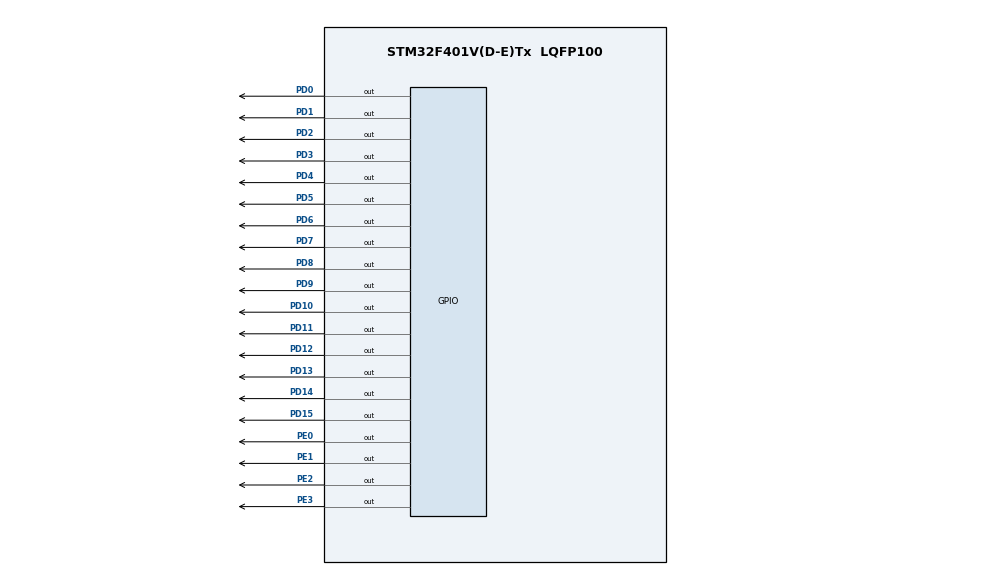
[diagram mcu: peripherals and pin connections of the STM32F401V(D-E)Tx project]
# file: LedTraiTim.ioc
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Mcu.Family=STM32F4
Mcu.Name=STM32F401V(D-E)Tx
Mcu.Package=LQFP100
NVIC.PriorityGroup=NVIC_PRIORITYGROUP_4
PD0.GPIO_Speed=GPIO_SPEED_FREQ_HIGH
PD0.PinState=GPIO_PIN_RESET
PD0.Signal=GPIO_Output
PD1.GPIO_Speed=GPIO_SPEED_FREQ_HIGH
PD1.Signal=GPIO_Output
PD10.GPIO_Speed=GPIO_SPEED_FREQ_HIGH
PD10.Signal=GPIO_Output
PD11.GPIO_Speed=GPIO_SPEED_FREQ_HIGH
PD11.Signal=GPIO_Output
PD12.GPIO_Speed=GPIO_SPEED_FREQ_HIGH
PD12.Signal=GPIO_Output
PD13.GPIO_Speed=GPIO_SPEED_FREQ_HIGH
PD13.Signal=GPIO_Output
PD14.GPIO_Speed=GPIO_SPEED_FREQ_HIGH
PD14.Signal=GPIO_Output
PD15.GPIO_Speed=GPIO_SPEED_FREQ_HIGH
PD15.Signal=GPIO_Output
PD2.GPIO_Speed=GPIO_SPEED_FREQ_HIGH
PD2.Signal=GPIO_Output
PD3.GPIO_Speed=GPIO_SPEED_FREQ_MEDIUM
PD3.Signal=GPIO_Output
PD4.GPIO_Speed=GPIO_SPEED_FREQ_HIGH
PD4.Signal=GPIO_Output
PD5.GPIO_Speed=GPIO_SPEED_FREQ_HIGH
PD5.Signal=GPIO_Output
PD6.GPIO_Speed=GPIO_SPEED_FREQ_HIGH
PD6.Signal=GPIO_Output
PD7.GPIO_Speed=GPIO_SPEED_FREQ_HIGH
PD7.Signal=GPIO_Output
PD8.GPIO_Speed=GPIO_SPEED_FREQ_HIGH
PD8.Signal=GPIO_Output
PD9.GPIO_Speed=GPIO_SPEED_FREQ_HIGH
PD9.Signal=GPIO_Output
PE0.GPIO_Speed=GPIO_SPEED_FREQ_HIGH
PE0.Signal=GPIO_Output
PE1.GPIO_Speed=GPIO_SPEED_FREQ_HIGH
PE1.Signal=GPIO_Output
PE2.GPIO_Speed=GPIO_SPEED_FREQ_HIGH
PE2.Signal=GPIO_Output
PE3.GPIO_Speed=GPIO_SPEED_FREQ_HIGH
PE3.Signal=GPIO_Output
PH0\ -\ OSC_IN.Mode=HSE-External-Oscillator
PH0\ -\ OSC_IN.Signal=RCC_OSC_IN
PH1\ -\ OSC_OUT.Mode=HSE-External-Oscillator
PH1\ -\ OSC_OUT.Signal=RCC_OSC_OUT
ProjectManager.HeapSize=0x200
ProjectManager.StackSize=0x400
ProjectManager.TargetToolchain=MDK-ARM V5.32
RCC.AHBFreq_Value=25000000
RCC.APB1Freq_Value=25000000
RCC.APB1TimFreq_Value=25000000
RCC.APB2Freq_Value=25000000
RCC.APB2TimFreq_Value=25000000
RCC.CortexFreq_Value=25000000
RCC.HCLKFreq_Value=25000000
RCC.HSE_VALUE=25000000
RCC.HSI_VALUE=16000000
RCC.LSE_VALUE=32768
RCC.SYSCLKFreq_VALUE=25000000
RCC.SYSCLKSource=RCC_SYSCLKSOURCE_HSE
RCC.VCOOutputFreq_Value=192000000
board=custom

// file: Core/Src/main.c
/* USER CODE BEGIN Header */
/**
  ******************************************************************************
  * @file           : main.c
  * @brief          : Main program body
  ******************************************************************************
  * @attention
  *
  * <h2><center>&copy; Copyright (c) 2021 STMicroelectronics.
  * All rights reserved.</center></h2>
  *
  * This software component is licensed by ST under BSD 3-Clause license,
  * the "License"; You may not use this file except in compliance with the
  * License. You may obtain a copy of the License at:
  *                        opensource.org/licenses/BSD-3-Clause
  *
  ******************************************************************************
  */
/* USER CODE END Header */
#include "main.h"

void SystemClock_Config(void);
static void MX_GPIO_Init(void);

void Sangden();
void Tatden();
void Sanglanluot1();
void Sanglanluot2();
int main(void)
{
  HAL_Init();
  SystemClock_Config();
  MX_GPIO_Init();
  while (1)
  {
		Sangden();
		HAL_Delay(100);
		Tatden();
		HAL_Delay(100);
		Sanglanluot1();
		HAL_Delay(100);
		Sanglanluot2();

  }
}

void Sangden(){
	HAL_GPIO_WritePin (GPIOD, GPIO_PIN_0, GPIO_PIN_SET);
	HAL_GPIO_WritePin (GPIOD, GPIO_PIN_1, GPIO_PIN_SET);
	HAL_GPIO_WritePin (GPIOD, GPIO_PIN_2, GPIO_PIN_SET);
	HAL_GPIO_WritePin (GPIOD, GPIO_PIN_3, GPIO_PIN_SET);
	HAL_GPIO_WritePin (GPIOD, GPIO_PIN_4, GPIO_PIN_SET);
	HAL_GPIO_WritePin (GPIOD, GPIO_PIN_5, GPIO_PIN_SET);
	HAL_GPIO_WritePin (GPIOD, GPIO_PIN_6, GPIO_PIN_SET);
	HAL_GPIO_WritePin (GPIOD, GPIO_PIN_7, GPIO_PIN_SET);
	HAL_GPIO_WritePin (GPIOD, GPIO_PIN_8, GPIO_PIN_SET);
	HAL_GPIO_WritePin (GPIOD, GPIO_PIN_9, GPIO_PIN_SET);
	HAL_GPIO_WritePin (GPIOD, GPIO_PIN_10, GPIO_PIN_SET);
	HAL_GPIO_WritePin (GPIOD, GPIO_PIN_11, GPIO_PIN_SET);
	HAL_GPIO_WritePin (GPIOD, GPIO_PIN_12, GPIO_PIN_SET);
	HAL_GPIO_WritePin (GPIOD, GPIO_PIN_13, GPIO_PIN_SET);
	HAL_GPIO_WritePin (GPIOD, GPIO_PIN_14, GPIO_PIN_SET);
	HAL_GPIO_WritePin (GPIOD, GPIO_PIN_15, GPIO_PIN_SET);

	HAL_GPIO_WritePin (GPIOE, GPIO_PIN_0, GPIO_PIN_SET);
	HAL_GPIO_WritePin (GPIOE, GPIO_PIN_1, GPIO_PIN_SET);
	HAL_GPIO_WritePin (GPIOE, GPIO_PIN_2, GPIO_PIN_SET);
	HAL_GPIO_WritePin (GPIOE, GPIO_PIN_3, GPIO_PIN_SET);
}

void Tatden(){
	HAL_GPIO_WritePin (GPIOD, GPIO_PIN_0, GPIO_PIN_RESET);
	HAL_GPIO_WritePin (GPIOD, GPIO_PIN_1, GPIO_PIN_RESET);
	HAL_GPIO_WritePin (GPIOD, GPIO_PIN_2, GPIO_PIN_RESET);
	HAL_GPIO_WritePin (GPIOD, GPIO_PIN_3, GPIO_PIN_RESET);
	HAL_GPIO_WritePin (GPIOD, GPIO_PIN_4, GPIO_PIN_RESET);
	HAL_GPIO_WritePin (GPIOD, GPIO_PIN_5, GPIO_PIN_RESET);
	HAL_GPIO_WritePin (GPIOD, GPIO_PIN_6, GPIO_PIN_RESET);
	HAL_GPIO_WritePin (GPIOD, GPIO_PIN_7, GPIO_PIN_RESET);
	HAL_GPIO_WritePin (GPIOD, GPIO_PIN_8, GPIO_PIN_RESET);
	HAL_GPIO_WritePin (GPIOD, GPIO_PIN_9, GPIO_PIN_RESET);
	HAL_GPIO_WritePin (GPIOD, GPIO_PIN_10, GPIO_PIN_RESET);
	HAL_GPIO_WritePin (GPIOD, GPIO_PIN_11, GPIO_PIN_RESET);
	HAL_GPIO_WritePin (GPIOD, GPIO_PIN_12, GPIO_PIN_RESET);
	HAL_GPIO_WritePin (GPIOD, GPIO_PIN_13, GPIO_PIN_RESET);
	HAL_GPIO_WritePin (GPIOD, GPIO_PIN_14, GPIO_PIN_RESET);
	HAL_GPIO_WritePin (GPIOD, GPIO_PIN_15, GPIO_PIN_RESET);

	HAL_GPIO_WritePin (GPIOE, GPIO_PIN_0, GPIO_PIN_RESET);
	HAL_GPIO_WritePin (GPIOE, GPIO_PIN_1, GPIO_PIN_RESET);
	HAL_GPIO_WritePin (GPIOE, GPIO_PIN_2, GPIO_PIN_RESET);
	HAL_GPIO_WritePin (GPIOE, GPIO_PIN_3, GPIO_PIN_RESET);
}

void Sanglanluot1(){
	Tatden();
	HAL_Delay(100);
	HAL_GPIO_WritePin (GPIOD, GPIO_PIN_0, GPIO_PIN_SET);
	HAL_Delay(100);
	HAL_GPIO_WritePin (GPIOD, GPIO_PIN_1, GPIO_PIN_SET);
	HAL_Delay(100);
	HAL_GPIO_WritePin (GPIOD, GPIO_PIN_2, GPIO_PIN_SET);
	HAL_Delay(100);
	HAL_GPIO_WritePin (GPIOD, GPIO_PIN_3, GPIO_PIN_SET);
	HAL_Delay(100);
	HAL_GPIO_WritePin (GPIOD, GPIO_PIN_4, GPIO_PIN_SET);
	HAL_Delay(100);
	HAL_GPIO_WritePin (GPIOD, GPIO_PIN_5, GPIO_PIN_SET);
	HAL_Delay(100);
	HAL_GPIO_WritePin (GPIOD, GPIO_PIN_6, GPIO_PIN_SET);
	HAL_Delay(100);
	HAL_GPIO_WritePin (GPIOD, GPIO_PIN_7, GPIO_PIN_SET);
	HAL_Delay(100);
	HAL_GPIO_WritePin (GPIOD, GPIO_PIN_8, GPIO_PIN_SET);
	HAL_Delay(100);
	HAL_GPIO_WritePin (GPIOD, GPIO_PIN_9, GPIO_PIN_SET);
	HAL_Delay(100);
	HAL_GPIO_WritePin (GPIOD, GPIO_PIN_10, GPIO_PIN_SET);
	HAL_Delay(100);
	HAL_GPIO_WritePin (GPIOD, GPIO_PIN_11, GPIO_PIN_SET);
	HAL_Delay(100);
	HAL_GPIO_WritePin (GPIOD, GPIO_PIN_12, GPIO_PIN_SET);
	HAL_Delay(100);
	HAL_GPIO_WritePin (GPIOD, GPIO_PIN_13, GPIO_PIN_SET);
	HAL_Delay(100);
	HAL_GPIO_WritePin (GPIOD, GPIO_PIN_14, GPIO_PIN_SET);
	HAL_Delay(100);
	HAL_GPIO_WritePin (GPIOD, GPIO_PIN_15, GPIO_PIN_SET);
	HAL_Delay(100);
	HAL_GPIO_WritePin (GPIOE, GPIO_PIN_0, GPIO_PIN_SET);
	HAL_Delay(100);
	HAL_GPIO_WritePin (GPIOE, GPIO_PIN_1, GPIO_PIN_SET);
	HAL_Delay(100);
	HAL_GPIO_WritePin (GPIOE, GPIO_PIN_2, GPIO_PIN_SET);
	HAL_Delay(100);
	HAL_GPIO_WritePin (GPIOE, GPIO_PIN_3, GPIO_PIN_SET);
	HAL_Delay(100);
}
void Sanglanluot2(){
		Tatden();
	HAL_Delay(100);

	HAL_GPIO_WritePin (GPIOD, GPIO_PIN_0, GPIO_PIN_SET);
	HAL_Delay(100);
	HAL_GPIO_WritePin (GPIOD, GPIO_PIN_0, GPIO_PIN_RESET);

	HAL_GPIO_WritePin (GPIOD, GPIO_PIN_1, GPIO_PIN_SET);
	HAL_Delay(100);
	HAL_GPIO_WritePin (GPIOD, GPIO_PIN_1, GPIO_PIN_RESET);

	HAL_GPIO_WritePin (GPIOD, GPIO_PIN_2, GPIO_PIN_SET);
	HAL_Delay(100);
	HAL_GPIO_WritePin (GPIOD, GPIO_PIN_2, GPIO_PIN_RESET);

	HAL_GPIO_WritePin (GPIOD, GPIO_PIN_3, GPIO_PIN_SET);
	HAL_Delay(100);
	HAL_GPIO_WritePin (GPIOD, GPIO_PIN_3, GPIO_PIN_RESET);

	HAL_GPIO_WritePin (GPIOD, GPIO_PIN_4, GPIO_PIN_SET);
	HAL_Delay(100);
	HAL_GPIO_WritePin (GPIOD, GPIO_PIN_4, GPIO_PIN_RESET);

	HAL_GPIO_WritePin (GPIOD, GPIO_PIN_5, GPIO_PIN_SET);
	HAL_Delay(100);
	HAL_GPIO_WritePin (GPIOD, GPIO_PIN_5, GPIO_PIN_RESET);

	HAL_GPIO_WritePin (GPIOD, GPIO_PIN_6, GPIO_PIN_SET);
	HAL_Delay(100);
	HAL_GPIO_WritePin (GPIOD, GPIO_PIN_6, GPIO_PIN_RESET);

	HAL_GPIO_WritePin (GPIOD, GPIO_PIN_7, GPIO_PIN_SET);
	HAL_Delay(100);
	HAL_GPIO_WritePin (GPIOD, GPIO_PIN_7, GPIO_PIN_RESET);

	HAL_GPIO_WritePin (GPIOD, GPIO_PIN_8, GPIO_PIN_SET);
	HAL_Delay(100);
	HAL_GPIO_WritePin (GPIOD, GPIO_PIN_8, GPIO_PIN_RESET);

	HAL_GPIO_WritePin (GPIOD, GPIO_PIN_9, GPIO_PIN_SET);
	HAL_Delay(100);
	HAL_GPIO_WritePin (GPIOD, GPIO_PIN_9, GPIO_PIN_RESET);

	HAL_GPIO_WritePin (GPIOD, GPIO_PIN_10, GPIO_PIN_SET);
	HAL_Delay(100);
	HAL_GPIO_WritePin (GPIOD, GPIO_PIN_10, GPIO_PIN_RESET);

	HAL_GPIO_WritePin (GPIOD, GPIO_PIN_11, GPIO_PIN_SET);
	HAL_Delay(100);
	HAL_GPIO_WritePin (GPIOD, GPIO_PIN_11, GPIO_PIN_RESET);

	HAL_GPIO_WritePin (GPIOD, GPIO_PIN_12, GPIO_PIN_SET);
	HAL_Delay(100);
	HAL_GPIO_WritePin (GPIOD, GPIO_PIN_12, GPIO_PIN_RESET);

	HAL_GPIO_WritePin (GPIOD, GPIO_PIN_13, GPIO_PIN_SET);
	HAL_Delay(100);
	HAL_GPIO_WritePin (GPIOD, GPIO_PIN_13, GPIO_PIN_RESET);

	HAL_GPIO_WritePin (GPIOD, GPIO_PIN_14, GPIO_PIN_SET);
	HAL_Delay(100);
	HAL_GPIO_WritePin (GPIOD, GPIO_PIN_14, GPIO_PIN_RESET);

	HAL_GPIO_WritePin (GPIOD, GPIO_PIN_15, GPIO_PIN_SET);
	HAL_Delay(100);
	HAL_GPIO_WritePin (GPIOD, GPIO_PIN_15, GPIO_PIN_RESET);

	HAL_GPIO_WritePin (GPIOE, GPIO_PIN_0, GPIO_PIN_SET);
	HAL_Delay(100);
	HAL_GPIO_WritePin (GPIOE, GPIO_PIN_0, GPIO_PIN_RESET);

	HAL_GPIO_WritePin (GPIOE, GPIO_PIN_1, GPIO_PIN_SET);
	HAL_Delay(100);
	HAL_GPIO_WritePin (GPIOE, GPIO_PIN_1, GPIO_PIN_RESET);

	HAL_GPIO_WritePin (GPIOE, GPIO_PIN_2, GPIO_PIN_SET);
	HAL_Delay(100);
	HAL_GPIO_WritePin (GPIOE, GPIO_PIN_2, GPIO_PIN_RESET);

	HAL_GPIO_WritePin (GPIOE, GPIO_PIN_3, GPIO_PIN_SET);
	HAL_Delay(100);
	HAL_GPIO_WritePin (GPIOE, GPIO_PIN_3, GPIO_PIN_RESET);
}

void SystemClock_Config(void)
{
  RCC_OscInitTypeDef RCC_OscInitStruct = {0};
  RCC_ClkInitTypeDef RCC_ClkInitStruct = {0};

  /** Configure the main internal regulator output voltage
  */
  __HAL_RCC_PWR_CLK_ENABLE();
  __HAL_PWR_VOLTAGESCALING_CONFIG(PWR_REGULATOR_VOLTAGE_SCALE2);
  /** Initializes the RCC Oscillators according to the specified parameters
  * in the RCC_OscInitTypeDef structure.
  */
  RCC_OscInitStruct.OscillatorType = RCC_OSCILLATORTYPE_HSE;
  RCC_OscInitStruct.HSEState = RCC_HSE_ON;
  RCC_OscInitStruct.PLL.PLLState = RCC_PLL_NONE;
  if (HAL_RCC_OscConfig(&RCC_OscInitStruct) != HAL_OK)
  {
    Error_Handler();
  }
  /** Initializes the CPU, AHB and APB buses clocks
  */
  RCC_ClkInitStruct.ClockType = RCC_CLOCKTYPE_HCLK|RCC_CLOCKTYPE_SYSCLK
                              |RCC_CLOCKTYPE_PCLK1|RCC_CLOCKTYPE_PCLK2;
  RCC_ClkInitStruct.SYSCLKSource = RCC_SYSCLKSOURCE_HSE;
  RCC_ClkInitStruct.AHBCLKDivider = RCC_SYSCLK_DIV1;
  RCC_ClkInitStruct.APB1CLKDivider = RCC_HCLK_DIV4;
  RCC_ClkInitStruct.APB2CLKDivider = RCC_HCLK_DIV2;

  if (HAL_RCC_ClockConfig(&RCC_ClkInitStruct, FLASH_LATENCY_0) != HAL_OK)
  {
    Error_Handler();
  }
}
static void MX_GPIO_Init(void)
{
  GPIO_InitTypeDef GPIO_InitStruct = {0};

  /* GPIO Ports Clock Enable */
  __HAL_RCC_GPIOE_CLK_ENABLE();
  __HAL_RCC_GPIOH_CLK_ENABLE();
  __HAL_RCC_GPIOD_CLK_ENABLE();

  /*Configure GPIO pin Output Level */
  HAL_GPIO_WritePin(GPIOE, GPIO_PIN_2|GPIO_PIN_3|GPIO_PIN_0|GPIO_PIN_1, GPIO_PIN_RESET);

  /*Configure GPIO pin Output Level */
  HAL_GPIO_WritePin(GPIOD, GPIO_PIN_8|GPIO_PIN_9|GPIO_PIN_10|GPIO_PIN_11
                          |GPIO_PIN_12|GPIO_PIN_13|GPIO_PIN_14|GPIO_PIN_15
                          |GPIO_PIN_0|GPIO_PIN_1|GPIO_PIN_2|GPIO_PIN_3
                          |GPIO_PIN_4|GPIO_PIN_5|GPIO_PIN_6|GPIO_PIN_7, GPIO_PIN_RESET);

  /*Configure GPIO pins : PE2 PE3 PE0 PE1 */
  GPIO_InitStruct.Pin = GPIO_PIN_2|GPIO_PIN_3|GPIO_PIN_0|GPIO_PIN_1;
  GPIO_InitStruct.Mode = GPIO_MODE_OUTPUT_PP;
  GPIO_InitStruct.Pull = GPIO_NOPULL;
  GPIO_InitStruct.Speed = GPIO_SPEED_FREQ_HIGH;
  HAL_GPIO_Init(GPIOE, &GPIO_InitStruct);

  /*Configure GPIO pins : PD8 PD9 PD10 PD11
                           PD12 PD13 PD14 PD15
                           PD0 PD1 PD2 PD4
                           PD5 PD6 PD7 */
  GPIO_InitStruct.Pin = GPIO_PIN_8|GPIO_PIN_9|GPIO_PIN_10|GPIO_PIN_11
                          |GPIO_PIN_12|GPIO_PIN_13|GPIO_PIN_14|GPIO_PIN_15
                          |GPIO_PIN_0|GPIO_PIN_1|GPIO_PIN_2|GPIO_PIN_4
                          |GPIO_PIN_5|GPIO_PIN_6|GPIO_PIN_7;
  GPIO_InitStruct.Mode = GPIO_MODE_OUTPUT_PP;
  GPIO_InitStruct.Pull = GPIO_NOPULL;
  GPIO_InitStruct.Speed = GPIO_SPEED_FREQ_HIGH;
  HAL_GPIO_Init(GPIOD, &GPIO_InitStruct);

  /*Configure GPIO pin : PD3 */
  GPIO_InitStruct.Pin = GPIO_PIN_3;
  GPIO_InitStruct.Mode = GPIO_MODE_OUTPUT_PP;
  GPIO_InitStruct.Pull = GPIO_NOPULL;
  GPIO_InitStruct.Speed = GPIO_SPEED_FREQ_MEDIUM;
  HAL_GPIO_Init(GPIOD, &GPIO_InitStruct);

}

void Error_Handler(void)
{
  __disable_irq();
  while (1)
  {
  }
}

/************************ (C) COPYRIGHT STMicroelectronics *****END OF FILE****/
